VERSION 5.8 ;
BUSBITCHARS "[]" ;
DIVIDERCHAR "/" ;
UNITS
    DATABASE MICRONS 2000 ;
END UNITS

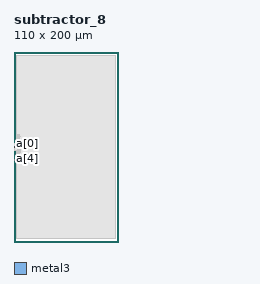
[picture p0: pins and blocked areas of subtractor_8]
MACRO subtractor_8
  FOREIGN subtractor_8 0 0 ;
  CLASS BLOCK ;
  SIZE 110 BY 200 ;
  PIN a[0]
    DIRECTION INPUT ;
    USE SIGNAL ;
    PORT
      LAYER metal3 ;
        RECT  0 103.355 0.07 103.425 ;
    END
  END a[0]
  PIN a[1]
    DIRECTION INPUT ;
    USE SIGNAL ;
    PORT
      LAYER metal3 ;
        RECT  0 99.995 0.07 100.065 ;
    END
  END a[1]
  PIN a[2]
    DIRECTION INPUT ;
    USE SIGNAL ;
    PORT
      LAYER metal3 ;
        RECT  0 97.195 0.07 97.265 ;
    END
  END a[2]
  PIN a[3]
    DIRECTION INPUT ;
    USE SIGNAL ;
    PORT
      LAYER metal3 ;
        RECT  0 98.035 0.07 98.105 ;
    END
  END a[3]
  PIN a[4]
    DIRECTION INPUT ;
    USE SIGNAL ;
    PORT
      LAYER metal3 ;
        RECT  0 96.635 0.07 96.705 ;
    END
  END a[4]
  PIN a[5]
    DIRECTION INPUT ;
    USE SIGNAL ;
    PORT
      LAYER metal3 ;
        RECT  0 100.835 0.07 100.905 ;
    END
  END a[5]
  PIN a[6]
    DIRECTION INPUT ;
    USE SIGNAL ;
    PORT
      LAYER metal3 ;
        RECT  0 101.115 0.07 101.185 ;
    END
  END a[6]
  PIN a[7]
    DIRECTION INPUT ;
    USE SIGNAL ;
    PORT
      LAYER metal3 ;
        RECT  0 99.435 0.07 99.505 ;
    END
  END a[7]
  PIN b[0]
    DIRECTION INPUT ;
    USE SIGNAL ;
    PORT
      LAYER metal3 ;
        RECT  0 97.755 0.07 97.825 ;
    END
  END b[0]
  PIN b[1]
    DIRECTION INPUT ;
    USE SIGNAL ;
    PORT
      LAYER metal3 ;
        RECT  0 101.675 0.07 101.745 ;
    END
  END b[1]
  PIN b[2]
    DIRECTION INPUT ;
    USE SIGNAL ;
    PORT
      LAYER metal3 ;
        RECT  0 100.275 0.07 100.345 ;
    END
  END b[2]
  PIN b[3]
    DIRECTION INPUT ;
    USE SIGNAL ;
    PORT
      LAYER metal3 ;
        RECT  0 99.155 0.07 99.225 ;
    END
  END b[3]
  PIN b[4]
    DIRECTION INPUT ;
    USE SIGNAL ;
    PORT
      LAYER metal3 ;
        RECT  0 100.555 0.07 100.625 ;
    END
  END b[4]
  PIN b[5]
    DIRECTION INPUT ;
    USE SIGNAL ;
    PORT
      LAYER metal3 ;
        RECT  0 102.515 0.07 102.585 ;
    END
  END b[5]
  PIN b[6]
    DIRECTION INPUT ;
    USE SIGNAL ;
    PORT
      LAYER metal3 ;
        RECT  0 101.395 0.07 101.465 ;
    END
  END b[6]
  PIN b[7]
    DIRECTION INPUT ;
    USE SIGNAL ;
    PORT
      LAYER metal3 ;
        RECT  0 98.875 0.07 98.945 ;
    END
  END b[7]
  PIN borrow
    DIRECTION OUTPUT ;
    USE SIGNAL ;
    PORT
      LAYER metal3 ;
        RECT  0 97.475 0.07 97.545 ;
    END
  END borrow
  PIN difference[0]
    DIRECTION OUTPUT ;
    USE SIGNAL ;
    PORT
      LAYER metal3 ;
        RECT  0 101.955 0.07 102.025 ;
    END
  END difference[0]
  PIN difference[1]
    DIRECTION OUTPUT ;
    USE SIGNAL ;
    PORT
      LAYER metal3 ;
        RECT  0 102.235 0.07 102.305 ;
    END
  END difference[1]
  PIN difference[2]
    DIRECTION OUTPUT ;
    USE SIGNAL ;
    PORT
      LAYER metal3 ;
        RECT  0 98.595 0.07 98.665 ;
    END
  END difference[2]
  PIN difference[3]
    DIRECTION OUTPUT ;
    USE SIGNAL ;
    PORT
      LAYER metal3 ;
        RECT  0 99.715 0.07 99.785 ;
    END
  END difference[3]
  PIN difference[4]
    DIRECTION OUTPUT ;
    USE SIGNAL ;
    PORT
      LAYER metal3 ;
        RECT  0 96.915 0.07 96.985 ;
    END
  END difference[4]
  PIN difference[5]
    DIRECTION OUTPUT ;
    USE SIGNAL ;
    PORT
      LAYER metal3 ;
        RECT  0 102.795 0.07 102.865 ;
    END
  END difference[5]
  PIN difference[6]
    DIRECTION OUTPUT ;
    USE SIGNAL ;
    PORT
      LAYER metal3 ;
        RECT  0 98.315 0.07 98.385 ;
    END
  END difference[6]
  PIN difference[7]
    DIRECTION OUTPUT ;
    USE SIGNAL ;
    PORT
      LAYER metal3 ;
        RECT  0 103.075 0.07 103.145 ;
    END
  END difference[7]
  OBS
    LAYER metal1 ;
     RECT  3.04 4.115 106.97 196.085 ;
    LAYER metal2 ;
     RECT  4.24 87.5 4.5 87.92 ;
     RECT  4.24 87.92 4.88 87.955 ;
     RECT  4.24 87.955 5.45 88.34 ;
     RECT  3.48 88.34 5.45 88.76 ;
     RECT  3.29 88.76 6.02 88.795 ;
     RECT  3.1 88.795 6.02 89.04 ;
     RECT  2.91 89.04 6.02 91.14 ;
     RECT  2.91 91.14 6.21 94.395 ;
     RECT  2.91 94.395 6.78 95.34 ;
     RECT  2.91 95.34 7.16 95.48 ;
     RECT  2.91 95.48 6.97 99.96 ;
     RECT  2.91 99.96 7.35 100.1 ;
     RECT  2.91 100.1 6.97 103.32 ;
     RECT  3.1 103.32 6.97 104.3 ;
     RECT  3.1 104.3 7.16 104.58 ;
     RECT  3.1 104.58 7.35 104.72 ;
     RECT  3.1 104.72 6.21 105.665 ;
     RECT  3.29 105.665 6.21 107.24 ;
     RECT  3.29 107.24 5.83 107.31 ;
     RECT  3.48 107.31 5.83 111.16 ;
     RECT  3.29 111.16 6.59 111.3 ;
     RECT  3.48 111.3 6.21 111.44 ;
     RECT  3.86 111.44 5.45 111.58 ;
     RECT  3.86 111.58 5.26 112.7 ;
     RECT  3.86 112.7 4.31 112.805 ;
     RECT  3.86 112.805 4.12 112.84 ;
    LAYER metal3 ;
     RECT  0.035 96.635 3.255 103.425 ;
     RECT  2.875 89.075 3.445 89.145 ;
     RECT  3.255 92.995 3.445 105.805 ;
     RECT  3.255 111.195 3.445 111.265 ;
     RECT  3.445 89.075 3.825 107.345 ;
     RECT  3.445 111.195 3.825 111.405 ;
     RECT  3.825 89.075 4.205 111.405 ;
     RECT  4.205 89.075 4.585 111.545 ;
     RECT  4.585 89.075 5.155 112.665 ;
     RECT  5.155 88.795 5.295 112.665 ;
     RECT  5.295 88.795 5.485 111.545 ;
     RECT  5.485 88.795 5.675 91.385 ;
     RECT  5.485 94.955 5.675 111.405 ;
     RECT  5.675 94.955 5.865 107.345 ;
     RECT  5.675 88.795 6.055 91.245 ;
     RECT  6.055 91.175 6.245 91.245 ;
     RECT  5.865 94.955 6.245 107.205 ;
     RECT  5.675 111.195 6.245 111.405 ;
     RECT  6.245 95.795 6.625 104.405 ;
     RECT  6.245 111.195 6.625 111.265 ;
     RECT  6.625 98.735 6.815 104.405 ;
     RECT  6.625 95.795 7.005 95.865 ;
     RECT  6.815 98.875 7.005 100.065 ;
     RECT  6.815 102.935 7.005 104.405 ;
     RECT  7.005 104.335 7.195 104.405 ;
     RECT  7.005 99.995 7.385 100.065 ;
  END
END subtractor_8
END LIBRARY
